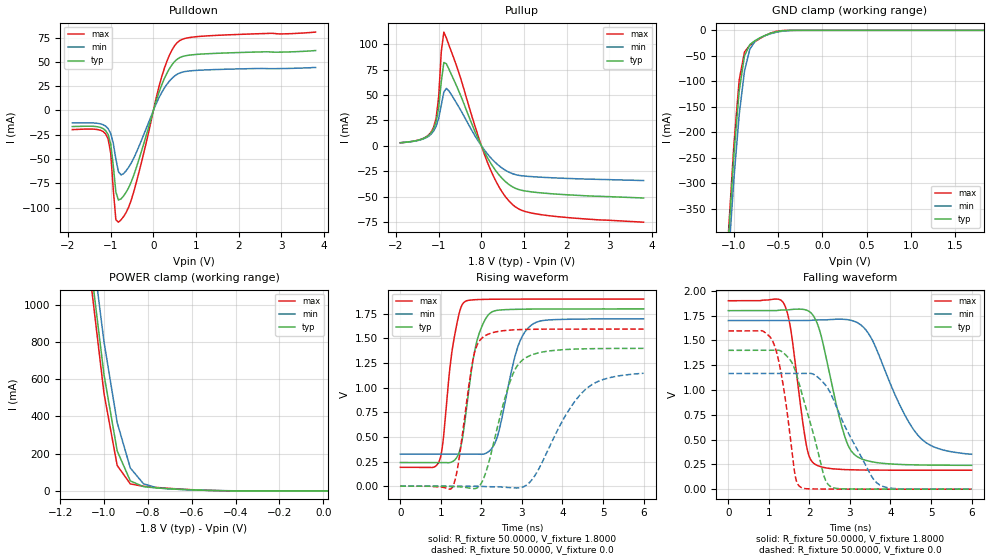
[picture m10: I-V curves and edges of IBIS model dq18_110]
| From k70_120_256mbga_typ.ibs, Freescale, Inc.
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|   Model dq18_110
[Model]  dq18_110
Model_type 3-state
Polarity   Non-Inverting
Enable   Active-High
Vmeas =  0.9000V
Cref =   5.0000pF
Rref =   50.0000
C_comp   2.8000pF   2.5000pF   3.3000pF
[Temperature Range]   25.0000   0.1250k   -40.0000
[Voltage Range]   1.8000V   1.7000V   1.9000V
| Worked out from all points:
|   slope of the pulldown table from 0 to 0.27 V, typ, clamps not added: 7.92 ohm
|   slope of the pullup table from 0 to 0.27 V, typ, clamps not added: 13.2 ohm
|   GND clamp passes 1 mA (typ) near -0.46 V on its own axis
|   POWER clamp passes 1 mA (typ) near -0.45 V on its own axis
|   rising waveform, R_fixture 50.0000, V_fixture 1.8000: 20-80 % time 341ps typ, 450ps min, 278ps max; typ from 0.24 V to 1.8 V
|   rising waveform, R_fixture 50.0000, V_fixture 0.0: 20-80 % time 551ps typ, 930ps min, 324ps max; typ from 0 V to 1.4 V
|   falling waveform, R_fixture 50.0000, V_fixture 1.8000: 20-80 % time 530ps typ, 901ps min, 328ps max; typ from 1.8 V to 0.24 V
|   falling waveform, R_fixture 50.0000, V_fixture 0.0: 20-80 % time 560ps typ, 838ps min, 337ps max; typ from 1.4 V to 0 V
[Pulldown]
|Voltage   I(typ)   I(min)   I(max)
-1.9V     -16.56mA   -12.76mA   -19.72mA
-1.12V    -20.71mA   -16.14mA   -24.09mA
-1.06V    -24.97mA   -18.75mA   -29.55mA
-1V       -34.7mA    -23.81mA   -44.17mA
-880mV    -83.97mA   -49.92mA   -112.5mA
-820mV    -92.25mA   -62.97mA   -115.1mA
-700mV    -88.17mA   -65.08mA   -109.4mA
-520mV    -73.71mA   -54.18mA   -92.4mA
200mV     26.91mA    18.89mA    35.48mA
380mV     43.37mA    30.48mA    57.35mA
560mV     52.89mA    37.37mA    69.96mA
3.8V      61.7mA     44.2mA     80.7mA
[Pullup]
|Voltage   I(typ)   I(min)   I(max)
-1.9V     3.1mA      3mA        3mA
-1.36V    7.19mA     6.82mA     7.37mA
-1.12V    16.72mA    14.49mA    18.27mA
-1.06V    23.85mA    19.35mA    27.54mA
-1V       37.85mA    27.45mA    48.91mA
-940mV    63.31mA    40.19mA    92.94mA
-880mV    82.12mA    53.08mA    112.1mA
-760mV    75.44mA    54.05mA    99.11mA
140mV     -11.48mA   -7.893mA   -16.13mA
680mV     -39.14mA   -26.63mA   -55.88mA
1.4V      -46.38mA   -30.94mA   -67.85mA
3.8V      -51.42mA   -34.22mA   -75.26mA
[GND_clamp]
|Voltage   I(typ)   I(min)   I(max)
-1.9V     -3.324A    -3.291A    -3.362A
-1.06V    -406mA     -446.9mA   -394mA
-1V       -244.6mA   -292.5mA   -224.9mA
-940mV    -119mA     -165.8mA   -97.67mA
-880mV    -50.08mA   -79.58mA   -42.55mA
-820mV    -28.04mA   -36.99mA   -29.42mA
-760mV    -20.01mA   -21.1mA    -22.02mA
-700mV    -14.3mA    -14.28mA   -15.42mA
-580mV    -5.492mA   -6.415mA   -5.005mA
-460mV    -1.014mA   -1.857mA   -600.6uA
-220mV    -979.5nA   -15.35uA   -59.46nA
1.82V     915.2pA    951.9nA    210.6pA
[POWER_clamp]
|Voltage   I(typ)   I(min)   I(max)
-1.9V     11.94A     11.89A     12.02A
-1.06V    1.204A     1.363A     1.122A
-1V       623.7mA    800mA      522.5mA
-940mV    215.1mA    367.1mA    136.6mA
-880mV    53.67mA    122.9mA    37.6mA
-820mV    23.13mA    38.48mA    24.96mA
-760mV    15.75mA    17.21mA    18.82mA
-640mV    7.758mA    7.284mA    9.105mA
-460mV    1.139mA    1.585mA    966.7uA
20mV      398.7pA    26.73nA    225pA
[Ramp]
| variable   typ   min   max
dV/dt_r  0.8397/0.5515n   0.6879/0.9301n   0.9573/0.3241n
dV/dt_f  0.9357/0.5301n   0.8090/0.9007n   1.0253/0.3280n
R_load = 50.0000
[Rising Waveform]
R_fixture= 50.0000
V_fixture= 1.8000
V_fixture_min= 1.7000
V_fixture_max= 1.9000
|time   V(typ)   V(min)   V(max)
0s        240.2mV    325.7mV    191.2mV
964.3ps   240.2mV    325.7mV    258.9mV
1.291ns   250.1mV    325.7mV    1.413V
1.585ns   633.7mV    325.7mV    1.872V
1.863ns   1.431V     325.9mV    1.894V
2.23ns    1.762V     370.7mV    1.898V
2.438ns   1.788V     569mV      1.899V
2.875ns   1.796V     1.385V     1.9V
3.185ns   1.798V     1.619V     1.9V
6ns       1.8V       1.7V       1.9V
[Rising Waveform]
R_fixture= 50.0000
V_fixture= 0.0
|time   V(typ)   V(min)   V(max)
0s        3.596nV    394.9nV    972.4pV
1.286ns   -4.934mV   650.8nV    -10.22mV
1.418ns   -5.46mV    -111.3nV   197mV
1.801ns   -25.1mV    162uV      1.304V
2.081ns   106.5mV    -4.234mV   1.525V
2.714ns   1.071V     -15.58mV   1.585V
3.032ns   1.287V     -7.353mV   1.591V
3.307ns   1.342V     99.36mV    1.593V
4.58ns    1.395V     987.8mV    1.595V
6ns       1.399V     1.147V     1.595V
[Falling Waveform]
R_fixture= 50.0000
V_fixture= 1.8000
V_fixture_min= 1.7000
V_fixture_max= 1.9000
|time   V(typ)   V(min)   V(max)
0s        1.8V       1.7V       1.9V
1.372ns   1.806V     1.7V       1.87V
1.541ns   1.811V     1.7V       1.609V
1.933ns   1.805V     1.7V       425.6mV
2.13ns    1.727V     1.705V     253.6mV
2.799ns   630.9mV    1.714V     198.6mV
3.097ns   353.5mV    1.694V     194.5mV
3.502ns   279.4mV    1.54V      192.3mV
4.667ns   244.1mV    548mV      191.2mV
6ns       240.5mV    351.7mV    191.2mV
[Falling Waveform]
R_fixture= 50.0000
V_fixture= 0.0
|time   V(typ)   V(min)   V(max)
0s        1.4V       1.166V     1.595V
832.5ps   1.4V       1.166V     1.597V
1.105ns   1.399V     1.166V     1.483V
1.349ns   1.377V     1.166V     1.059V
1.655ns   1.191V     1.166V     122.3mV
1.773ns   1.026V     1.166V     22.93mV
2.365ns   125.4mV    1.065V     949.5uV
2.522ns   26.32mV    965.9mV    623uV
3.729ns   450.8uV    43.73mV    21.9uV
6ns       5.063uV    236.9uV    27.28nV
